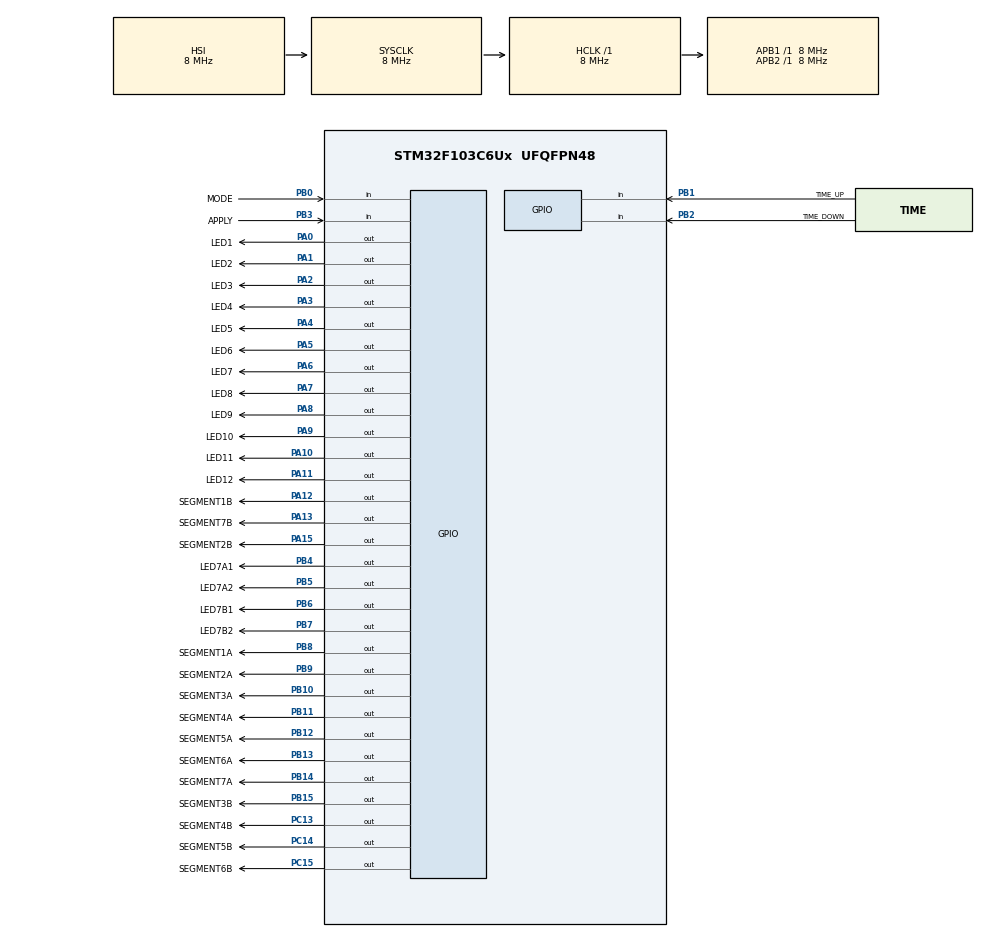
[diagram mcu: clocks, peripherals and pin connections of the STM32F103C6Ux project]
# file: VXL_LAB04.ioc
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Mcu.Family=STM32F1
Mcu.Name=STM32F103C6Ux
Mcu.Package=UFQFPN48
NVIC.PriorityGroup=NVIC_PRIORITYGROUP_4
NVIC.TIM2_IRQn=true\:0\:0\:false\:false\:true\:true\:true\:true
PA0-WKUP.GPIO_Label=LED1
PA0-WKUP.Signal=GPIO_Output
PA1.GPIO_Label=LED2
PA1.Signal=GPIO_Output
PA10.GPIO_Label=LED11
PA10.Signal=GPIO_Output
PA11.GPIO_Label=LED12
PA11.Signal=GPIO_Output
PA12.GPIO_Label=SEGMENT1B
PA12.Signal=GPIO_Output
PA13.GPIO_Label=SEGMENT7B
PA13.Signal=GPIO_Output
PA15.GPIO_Label=SEGMENT2B
PA15.Signal=GPIO_Output
PA2.GPIO_Label=LED3
PA2.Signal=GPIO_Output
PA3.GPIO_Label=LED4
PA3.Signal=GPIO_Output
PA4.GPIO_Label=LED5
PA4.Signal=GPIO_Output
PA5.GPIO_Label=LED6
PA5.Signal=GPIO_Output
PA6.GPIO_Label=LED7
PA6.Signal=GPIO_Output
PA7.GPIO_Label=LED8
PA7.Signal=GPIO_Output
PA8.GPIO_Label=LED9
PA8.Signal=GPIO_Output
PA9.GPIO_Label=LED10
PA9.Signal=GPIO_Output
PB0.GPIO_Label=MODE
PB0.GPIO_PuPd=GPIO_PULLUP
PB0.Signal=GPIO_Input
PB1.GPIO_Label=TIME_UP
PB1.GPIO_PuPd=GPIO_PULLUP
PB1.Signal=GPIO_Input
PB10.GPIO_Label=SEGMENT3A
PB10.Signal=GPIO_Output
PB11.GPIO_Label=SEGMENT4A
PB11.Signal=GPIO_Output
PB12.GPIO_Label=SEGMENT5A
PB12.Signal=GPIO_Output
PB13.GPIO_Label=SEGMENT6A
PB13.Signal=GPIO_Output
PB14.GPIO_Label=SEGMENT7A
PB14.Signal=GPIO_Output
PB15.GPIO_Label=SEGMENT3B
PB15.Signal=GPIO_Output
PB2.GPIO_Label=TIME_DOWN
PB2.GPIO_PuPd=GPIO_PULLUP
PB2.Signal=GPIO_Input
PB3.GPIO_Label=APPLY
PB3.GPIO_PuPd=GPIO_PULLUP
PB3.Signal=GPIO_Input
PB4.GPIO_Label=LED7A1
PB4.Signal=GPIO_Output
PB5.GPIO_Label=LED7A2
PB5.Signal=GPIO_Output
PB6.GPIO_Label=LED7B1
PB6.Signal=GPIO_Output
PB7.GPIO_Label=LED7B2
PB7.Signal=GPIO_Output
PB8.GPIO_Label=SEGMENT1A
PB8.Signal=GPIO_Output
PB9.GPIO_Label=SEGMENT2A
PB9.Signal=GPIO_Output
PC13-TAMPER-RTC.GPIO_Label=SEGMENT4B
PC13-TAMPER-RTC.Signal=GPIO_Output
PC14-OSC32_IN.GPIO_Label=SEGMENT5B
PC14-OSC32_IN.Signal=GPIO_Output
PC15-OSC32_OUT.GPIO_Label=SEGMENT6B
PC15-OSC32_OUT.Signal=GPIO_Output
ProjectManager.HeapSize=0x200
ProjectManager.StackSize=0x400
ProjectManager.TargetToolchain=STM32CubeIDE
RCC.AHBFreq_Value=8000000
RCC.APB1Freq_Value=8000000
RCC.APB1TimFreq_Value=8000000
RCC.APB2Freq_Value=8000000
RCC.APB2TimFreq_Value=8000000
RCC.HCLKFreq_Value=8000000
RCC.SYSCLKFreq_VALUE=8000000
RCC.USBFreq_Value=8000000
TIM2.Period=9
TIM2.Prescaler=7999
VP_SYS_VS_ND.Mode=No_Debug
VP_TIM2_VS_ClockSourceINT.Mode=Internal
board=custom

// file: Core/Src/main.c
/* USER CODE BEGIN Header */
/**
  ******************************************************************************
  * @file           : main.c
  * @brief          : Main program body
  ******************************************************************************
  * @attention
  *
  * <h2><center>&copy; Copyright (c) 2021 STMicroelectronics.
  * All rights reserved.</center></h2>
  *
  * This software component is licensed by ST under BSD 3-Clause license,
  * the "License"; You may not use this file except in compliance with the
  * License. You may obtain a copy of the License at:
  *                        opensource.org/licenses/BSD-3-Clause
  *
  ******************************************************************************
  */
/* USER CODE END Header */
#include "main.h"
#include "sched.h"

TIM_HandleTypeDef htim2;

void SystemClock_Config(void);
static void MX_GPIO_Init(void);
static void MX_TIM2_Init(void);

/* USER CODE BEGIN 0 */
void ledDisplay() {
	HAL_GPIO_TogglePin(Led_Test_System_GPIO_Port, Led_Test_System_Pin);
}
/* USER CODE END 0 */

int main(void)
{

  /* MCU Configuration--------------------------------------------------------*/

  /* Reset of all peripherals, Initializes the Flash interface and the Systick. */
  HAL_Init();

  /* Configure the system clock */
  SystemClock_Config();

  /* Initialize all configured peripherals */
  MX_GPIO_Init();
  MX_TIM2_Init();
  /* USER CODE BEGIN 2 */
  SCH_Init();

  /* USER CODE END 2 */

  /* Infinite loop */
  /* USER CODE BEGIN WHILE */
  SCH_Add_Task(ledDisplay, 0, 1000);
  while (1)
  {
    /* USER CODE END WHILE */
	  SCH_Dispatch_Task();
  }
}

void SystemClock_Config(void)
{
  RCC_OscInitTypeDef RCC_OscInitStruct = {0};
  RCC_ClkInitTypeDef RCC_ClkInitStruct = {0};

  /** Initializes the RCC Oscillators according to the specified parameters
  * in the RCC_OscInitTypeDef structure.
  */
  RCC_OscInitStruct.OscillatorType = RCC_OSCILLATORTYPE_HSI;
  RCC_OscInitStruct.HSIState = RCC_HSI_ON;
  RCC_OscInitStruct.HSICalibrationValue = RCC_HSICALIBRATION_DEFAULT;
  RCC_OscInitStruct.PLL.PLLState = RCC_PLL_NONE;
  if (HAL_RCC_OscConfig(&RCC_OscInitStruct) != HAL_OK)
  {
    Error_Handler();
  }
  /** Initializes the CPU, AHB and APB buses clocks
  */
  RCC_ClkInitStruct.ClockType = RCC_CLOCKTYPE_HCLK|RCC_CLOCKTYPE_SYSCLK
                              |RCC_CLOCKTYPE_PCLK1|RCC_CLOCKTYPE_PCLK2;
  RCC_ClkInitStruct.SYSCLKSource = RCC_SYSCLKSOURCE_HSI;
  RCC_ClkInitStruct.AHBCLKDivider = RCC_SYSCLK_DIV1;
  RCC_ClkInitStruct.APB1CLKDivider = RCC_HCLK_DIV1;
  RCC_ClkInitStruct.APB2CLKDivider = RCC_HCLK_DIV1;

  if (HAL_RCC_ClockConfig(&RCC_ClkInitStruct, FLASH_LATENCY_0) != HAL_OK)
  {
    Error_Handler();
  }
}

static void MX_TIM2_Init(void)
{

  TIM_ClockConfigTypeDef sClockSourceConfig = {0};
  TIM_MasterConfigTypeDef sMasterConfig = {0};

  htim2.Instance = TIM2;
  htim2.Init.Prescaler = 7999;
  htim2.Init.CounterMode = TIM_COUNTERMODE_UP;
  htim2.Init.Period = 9;
  htim2.Init.ClockDivision = TIM_CLOCKDIVISION_DIV1;
  htim2.Init.AutoReloadPreload = TIM_AUTORELOAD_PRELOAD_DISABLE;
  if (HAL_TIM_Base_Init(&htim2) != HAL_OK)
  {
    Error_Handler();
  }
  sClockSourceConfig.ClockSource = TIM_CLOCKSOURCE_INTERNAL;
  if (HAL_TIM_ConfigClockSource(&htim2, &sClockSourceConfig) != HAL_OK)
  {
    Error_Handler();
  }
  sMasterConfig.MasterOutputTrigger = TIM_TRGO_RESET;
  sMasterConfig.MasterSlaveMode = TIM_MASTERSLAVEMODE_DISABLE;
  if (HAL_TIMEx_MasterConfigSynchronization(&htim2, &sMasterConfig) != HAL_OK)
  {
    Error_Handler();
  }

}

static void MX_GPIO_Init(void)
{
  GPIO_InitTypeDef GPIO_InitStruct = {0};

  /* GPIO Ports Clock Enable */
  __HAL_RCC_GPIOA_CLK_ENABLE();
  __HAL_RCC_GPIOB_CLK_ENABLE();

  /*Configure GPIO pin Output Level */
  HAL_GPIO_WritePin(GPIOA, Led_Test_System_Pin|Led_Test_Timer_Pin|Dot_Pin|Led_5_Pin
                          |En0_Pin|En1_Pin|En2_Pin|En3_Pin, GPIO_PIN_RESET);

  /*Configure GPIO pin Output Level */
  HAL_GPIO_WritePin(GPIOB, Led7_a_Pin|Led7_b_Pin|Led7_c_Pin|Led7_d_Pin
                          |Led7_e_Pin|Led7_f_Pin|Led7_g_Pin, GPIO_PIN_RESET);

  /*Configure GPIO pins : Led_Test_System_Pin Led_Test_Timer_Pin Dot_Pin Led_5_Pin
                           En0_Pin En1_Pin En2_Pin En3_Pin */
  GPIO_InitStruct.Pin = Led_Test_System_Pin|Led_Test_Timer_Pin|Dot_Pin|Led_5_Pin
                          |En0_Pin|En1_Pin|En2_Pin|En3_Pin;
  GPIO_InitStruct.Mode = GPIO_MODE_OUTPUT_PP;
  GPIO_InitStruct.Pull = GPIO_NOPULL;
  GPIO_InitStruct.Speed = GPIO_SPEED_FREQ_LOW;
  HAL_GPIO_Init(GPIOA, &GPIO_InitStruct);

  /*Configure GPIO pins : Led7_a_Pin Led7_b_Pin Led7_c_Pin Led7_d_Pin
                           Led7_e_Pin Led7_f_Pin Led7_g_Pin */
  GPIO_InitStruct.Pin = Led7_a_Pin|Led7_b_Pin|Led7_c_Pin|Led7_d_Pin
                          |Led7_e_Pin|Led7_f_Pin|Led7_g_Pin;
  GPIO_InitStruct.Mode = GPIO_MODE_OUTPUT_PP;
  GPIO_InitStruct.Pull = GPIO_NOPULL;
  GPIO_InitStruct.Speed = GPIO_SPEED_FREQ_LOW;
  HAL_GPIO_Init(GPIOB, &GPIO_InitStruct);

}

void Error_Handler(void)
{
  __disable_irq();
  while (1)
  {
  }
}

/************************ (C) COPYRIGHT STMicroelectronics *****END OF FILE****/
